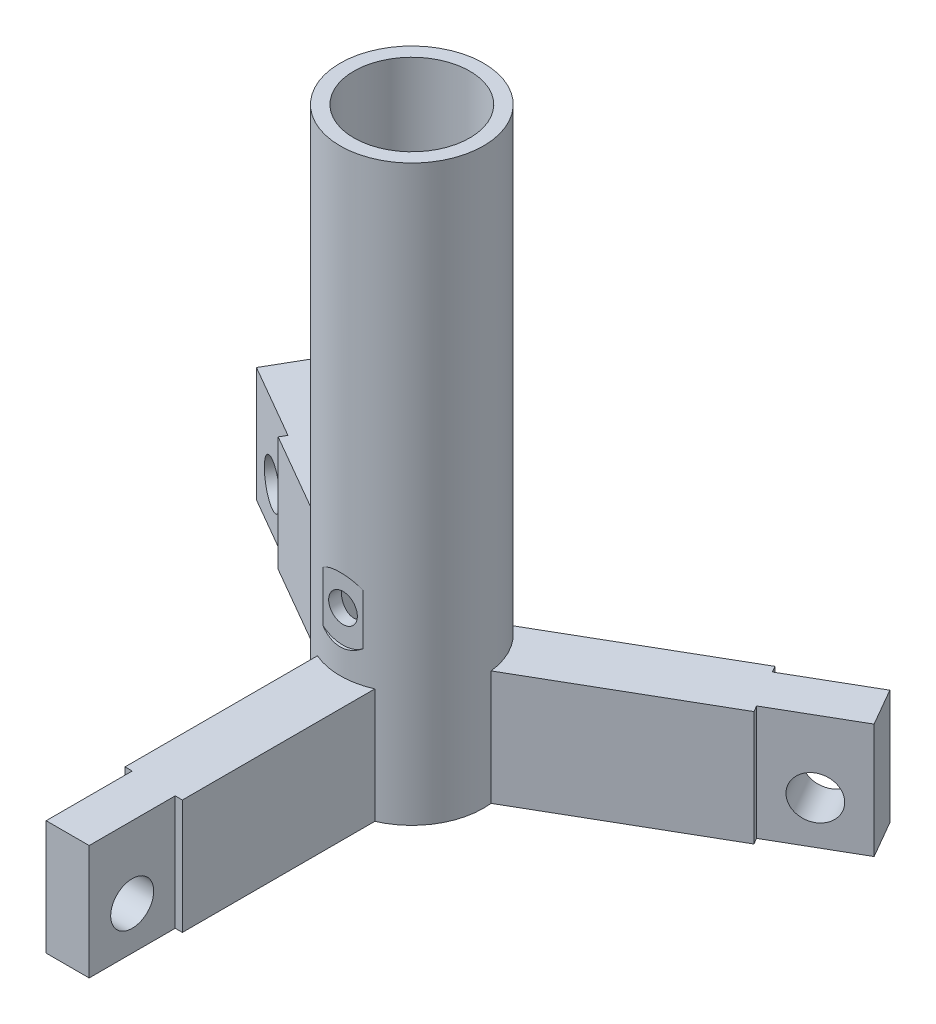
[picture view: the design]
ISO-10303-21;
HEADER;
FILE_DESCRIPTION(('STEP AP214'),'2;1');
FILE_NAME('part.step','',(''),(''),'','','');
FILE_SCHEMA(('AUTOMOTIVE_DESIGN { 1 0 10303 214 1 1 1 1 }'));
ENDSEC;
DATA;
#1=APPLICATION_CONTEXT('core data for automotive mechanical design processes');
#2=APPLICATION_PROTOCOL_DEFINITION('international standard','automotive_design',2000,#1);
#3=PRODUCT_CONTEXT('',#1,'mechanical');
#4=PRODUCT('Part','Part','',(#3));
#5=PRODUCT_RELATED_PRODUCT_CATEGORY('part','',(#4));
#6=PRODUCT_DEFINITION_FORMATION('','',#4);
#7=PRODUCT_DEFINITION_CONTEXT('part definition',#1,'design');
#8=PRODUCT_DEFINITION('design','',#6,#7);
#9=PRODUCT_DEFINITION_SHAPE('','',#8);
#10=(LENGTH_UNIT() NAMED_UNIT(*) SI_UNIT(.MILLI.,.METRE.));
#11=(NAMED_UNIT(*) PLANE_ANGLE_UNIT() SI_UNIT($,.RADIAN.));
#12=(NAMED_UNIT(*) SI_UNIT($,.STERADIAN.) SOLID_ANGLE_UNIT());
#13=UNCERTAINTY_MEASURE_WITH_UNIT(LENGTH_MEASURE(1.E-05),#10,'distance_accuracy_value','');
#14=(GEOMETRIC_REPRESENTATION_CONTEXT(3) GLOBAL_UNCERTAINTY_ASSIGNED_CONTEXT((#13)) GLOBAL_UNIT_ASSIGNED_CONTEXT((#10,
#11,#12)) REPRESENTATION_CONTEXT('',''));
#15=CARTESIAN_POINT('',(0.,0.,0.));
#16=DIRECTION('',(0.,0.,1.));
#17=DIRECTION('',(1.,0.,0.));
#18=AXIS2_PLACEMENT_3D('',#15,#16,#17);
#19=CARTESIAN_POINT('',(0.,38.1,15.24));
#20=DIRECTION('',(0.,0.,1.));
#21=DIRECTION('',(0.,-1.,0.));
#22=AXIS2_PLACEMENT_3D('',#19,#20,#21);
#23=PLANE('',#22);
#24=DIRECTION('',(0.,-1.,0.));
#25=VECTOR('',#24,1.);
#26=CARTESIAN_POINT('',(-4.44500000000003,127.,15.24));
#27=LINE('',#26,#25);
#28=CARTESIAN_POINT('',(-4.44500000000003,43.7005272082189,15.24));
#29=VERTEX_POINT('',#28);
#30=CARTESIAN_POINT('',(-4.44500000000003,32.4994727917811,15.24));
#31=VERTEX_POINT('',#30);
#32=EDGE_CURVE('E11',#29,#31,#27,.T.);
#33=ORIENTED_EDGE('',*,*,#32,.T.);
#34=CARTESIAN_POINT('',(0.,38.1,15.24));
#35=DIRECTION('',(0.,0.,1.));
#36=DIRECTION('',(0.,-1.,0.));
#37=AXIS2_PLACEMENT_3D('',#34,#35,#36);
#38=CIRCLE('',#37,7.1501);
#39=CARTESIAN_POINT('',(4.44500000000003,32.4994727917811,15.24));
#40=VERTEX_POINT('',#39);
#41=EDGE_CURVE('E215',#31,#40,#38,.T.);
#42=ORIENTED_EDGE('',*,*,#41,.T.);
#43=DIRECTION('',(0.,-1.,0.));
#44=VECTOR('',#43,1.);
#45=CARTESIAN_POINT('',(4.44500000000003,127.,15.24));
#46=LINE('',#45,#44);
#47=CARTESIAN_POINT('',(4.44500000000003,43.7005272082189,15.24));
#48=VERTEX_POINT('',#47);
#49=EDGE_CURVE('E46',#40,#48,#46,.F.);
#50=ORIENTED_EDGE('',*,*,#49,.T.);
#51=EDGE_CURVE('E213',#48,#29,#38,.T.);
#52=ORIENTED_EDGE('',*,*,#51,.T.);
#53=EDGE_LOOP('',(#33,#42,#50,#52));
#54=FACE_BOUND('',#53,.T.);
#55=CARTESIAN_POINT('',(0.,38.1,15.24));
#56=DIRECTION('',(0.,0.,1.));
#57=DIRECTION('',(0.,-1.,0.));
#58=AXIS2_PLACEMENT_3D('',#55,#56,#57);
#59=CIRCLE('',#58,3.17499725);
#60=CARTESIAN_POINT('',(0.,34.92500275,15.24));
#61=VERTEX_POINT('',#60);
#62=EDGE_CURVE('E590',#61,#61,#59,.T.);
#63=ORIENTED_EDGE('',*,*,#62,.F.);
#64=EDGE_LOOP('',(#63));
#65=FACE_BOUND('',#64,.T.);
#66=ADVANCED_FACE('F32',(#54,#65),#23,.T.);
#67=CARTESIAN_POINT('',(0.,127.,0.));
#68=DIRECTION('',(0.,-1.,0.));
#69=DIRECTION('',(0.,0.,-1.));
#70=AXIS2_PLACEMENT_3D('',#67,#68,#69);
#71=CYLINDRICAL_SURFACE('',#70,12.827);
#72=CARTESIAN_POINT('',(0.,0.,0.));
#73=DIRECTION('',(0.,1.,0.));
#74=DIRECTION('',(0.,0.,1.));
#75=AXIS2_PLACEMENT_3D('',#72,#73,#74);
#76=CIRCLE('',#75,12.827);
#77=CARTESIAN_POINT('',(0.,0.,12.827));
#78=VERTEX_POINT('',#77);
#79=EDGE_CURVE('E749',#78,#78,#76,.T.);
#80=ORIENTED_EDGE('',*,*,#79,.F.);
#81=EDGE_LOOP('',(#80));
#82=FACE_BOUND('',#81,.T.);
#83=CARTESIAN_POINT('',(0.,127.,0.));
#84=DIRECTION('',(0.,1.,0.));
#85=DIRECTION('',(0.,0.,1.));
#86=AXIS2_PLACEMENT_3D('',#83,#84,#85);
#87=CIRCLE('',#86,12.827);
#88=CARTESIAN_POINT('',(0.,127.,12.827));
#89=VERTEX_POINT('',#88);
#90=EDGE_CURVE('E770',#89,#89,#87,.T.);
#91=ORIENTED_EDGE('',*,*,#90,.T.);
#92=EDGE_LOOP('',(#91));
#93=FACE_BOUND('',#92,.T.);
#94=CARTESIAN_POINT('',(0.,34.92500275,12.827));
#95=CARTESIAN_POINT('',(0.175477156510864,34.9250077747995,12.8269969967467));
#96=CARTESIAN_POINT('',(0.351010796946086,34.9395992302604,12.823363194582));
#97=CARTESIAN_POINT('',(0.697051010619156,34.9974943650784,12.8092192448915));
#98=CARTESIAN_POINT('',(0.867554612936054,35.0408146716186,12.7987051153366));
#99=CARTESIAN_POINT('',(1.19848733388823,35.1546952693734,12.7719653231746));
#100=CARTESIAN_POINT('',(1.35892815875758,35.2252231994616,12.7557464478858));
#101=CARTESIAN_POINT('',(1.66570059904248,35.3914040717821,12.7193264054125));
#102=CARTESIAN_POINT('',(1.81203180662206,35.4870577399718,12.6991251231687));
#103=CARTESIAN_POINT('',(2.0893903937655,35.702818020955,12.6564783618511));
#104=CARTESIAN_POINT('',(2.22009183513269,35.8233369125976,12.6339988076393));
#105=CARTESIAN_POINT('',(2.45964846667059,36.0845236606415,12.5895565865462));
#106=CARTESIAN_POINT('',(2.56850123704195,36.2251937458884,12.5675939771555));
#107=CARTESIAN_POINT('',(2.76279553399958,36.5252104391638,12.526329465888));
#108=CARTESIAN_POINT('',(2.84787393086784,36.6847987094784,12.5070708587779));
#109=CARTESIAN_POINT('',(2.98986969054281,37.0165657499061,12.4738912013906));
#110=CARTESIAN_POINT('',(3.04679145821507,37.1887425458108,12.4599693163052));
#111=CARTESIAN_POINT('',(3.12974912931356,37.537219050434,12.4393893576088));
#112=CARTESIAN_POINT('',(3.15637034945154,37.7133711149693,12.4325938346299));
#113=CARTESIAN_POINT('',(3.17979416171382,38.0677620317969,12.4266244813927));
#114=CARTESIAN_POINT('',(3.17660150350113,38.2460005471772,12.4274494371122));
#115=CARTESIAN_POINT('',(3.14095552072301,38.5950303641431,12.4365041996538));
#116=CARTESIAN_POINT('',(3.10919816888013,38.7658980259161,12.4445578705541));
#117=CARTESIAN_POINT('',(3.0184338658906,39.099801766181,12.4668821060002));
#118=CARTESIAN_POINT('',(2.95942500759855,39.2628372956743,12.4811531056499));
#119=CARTESIAN_POINT('',(2.81523584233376,39.5783225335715,12.5144666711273));
#120=CARTESIAN_POINT('',(2.72980170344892,39.7306511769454,12.5335551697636));
#121=CARTESIAN_POINT('',(2.53536473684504,40.0190604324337,12.5743268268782));
#122=CARTESIAN_POINT('',(2.42635785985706,40.1551382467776,12.5960104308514));
#123=CARTESIAN_POINT('',(2.18425803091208,40.4111730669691,12.64027191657));
#124=CARTESIAN_POINT('',(2.05057737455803,40.5305736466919,12.6628578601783));
#125=CARTESIAN_POINT('',(1.76482059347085,40.7453665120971,12.7058325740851));
#126=CARTESIAN_POINT('',(1.61274392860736,40.8407580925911,12.7262212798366));
#127=CARTESIAN_POINT('',(1.2937277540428,41.0050237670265,12.7626025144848));
#128=CARTESIAN_POINT('',(1.12674066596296,41.0738089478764,12.7785802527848));
#129=CARTESIAN_POINT('',(0.783090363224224,41.1821778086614,12.804231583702));
#130=CARTESIAN_POINT('',(0.606428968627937,41.2217669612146,12.8139063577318));
#131=CARTESIAN_POINT('',(0.253203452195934,41.2697735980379,12.8256874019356));
#132=CARTESIAN_POINT('',(0.0767483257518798,41.2789490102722,12.827977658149));
#133=CARTESIAN_POINT('',(-0.275175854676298,41.2679444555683,12.8252549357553));
#134=CARTESIAN_POINT('',(-0.450644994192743,41.2477670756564,12.8202426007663));
#135=CARTESIAN_POINT('',(-0.792992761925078,41.1792548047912,12.8035956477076));
#136=CARTESIAN_POINT('',(-0.959959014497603,41.1313320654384,12.7920580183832));
#137=CARTESIAN_POINT('',(-1.28347476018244,41.0091590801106,12.7636599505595));
#138=CARTESIAN_POINT('',(-1.44002321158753,40.9349062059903,12.7467989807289));
#139=CARTESIAN_POINT('',(-1.74128504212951,40.7607026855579,12.7091826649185));
#140=CARTESIAN_POINT('',(-1.885743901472,40.6603257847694,12.688364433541));
#141=CARTESIAN_POINT('',(-2.15603644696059,40.4372697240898,12.6452442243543));
#142=CARTESIAN_POINT('',(-2.28186697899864,40.314586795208,12.6229419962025));
#143=CARTESIAN_POINT('',(-2.51444398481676,40.0468851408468,12.5787072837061));
#144=CARTESIAN_POINT('',(-2.62065929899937,39.9014005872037,12.5567965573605));
#145=CARTESIAN_POINT('',(-2.80716625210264,39.5942237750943,12.5164247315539));
#146=CARTESIAN_POINT('',(-2.88745904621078,39.4325322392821,12.4979634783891));
#147=CARTESIAN_POINT('',(-3.01924661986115,39.0984031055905,12.4667825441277));
#148=CARTESIAN_POINT('',(-3.0709120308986,38.9260361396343,12.4540289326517));
#149=CARTESIAN_POINT('',(-3.14443320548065,38.5746997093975,12.4356717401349));
#150=CARTESIAN_POINT('',(-3.16629533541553,38.3957316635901,12.4300666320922));
#151=CARTESIAN_POINT('',(-3.17926168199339,38.0416739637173,12.4267558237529));
#152=CARTESIAN_POINT('',(-3.17121422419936,37.8666169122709,12.4288322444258));
#153=CARTESIAN_POINT('',(-3.12652759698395,37.5204389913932,12.4401477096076));
#154=CARTESIAN_POINT('',(-3.08988898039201,37.3493180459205,12.449386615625));
#155=CARTESIAN_POINT('',(-2.98951914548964,37.0167714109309,12.4738658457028));
#156=CARTESIAN_POINT('',(-2.92594407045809,36.8552958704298,12.4890715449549));
#157=CARTESIAN_POINT('',(-2.77363006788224,36.545189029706,12.5237765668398));
#158=CARTESIAN_POINT('',(-2.68488771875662,36.3965594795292,12.5432764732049));
#159=CARTESIAN_POINT('',(-2.48208584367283,36.1122572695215,12.5849965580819));
#160=CARTESIAN_POINT('',(-2.3674363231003,35.9770137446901,12.6072735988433));
#161=CARTESIAN_POINT('',(-2.11722825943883,35.7274091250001,12.651695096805));
#162=CARTESIAN_POINT('',(-1.98166477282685,35.6130529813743,12.6738395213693));
#163=CARTESIAN_POINT('',(-1.69058803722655,35.4065031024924,12.7159671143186));
#164=CARTESIAN_POINT('',(-1.53476480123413,35.3147363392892,12.7359052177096));
#165=CARTESIAN_POINT('',(-1.20942520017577,35.1588466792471,12.7709004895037));
#166=CARTESIAN_POINT('',(-1.03991889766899,35.0947036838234,12.7859612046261));
#167=CARTESIAN_POINT('',(-0.725560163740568,35.0055663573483,12.8072389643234));
#168=CARTESIAN_POINT('',(-0.582224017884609,34.9754196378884,12.8145988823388));
#169=CARTESIAN_POINT('',(-0.29260486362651,34.935136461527,12.824480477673));
#170=CARTESIAN_POINT('',(-0.146322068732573,34.9249985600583,12.8270025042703));
#171=CARTESIAN_POINT('',(0.,34.92500275,12.827));
#172=B_SPLINE_CURVE_WITH_KNOTS('',3,(#94,#95,#96,#97,#98,#99,#100,#101,#102,#103,#104,#105,#106,
#107,#108,#109,#110,#111,#112,#113,#114,#115,#116,#117,#118,#119,#120,#121,#122,#123,#124,#125,
#126,#127,#128,#129,#130,#131,#132,#133,#134,#135,#136,#137,#138,#139,#140,#141,#142,#143,#144,
#145,#146,#147,#148,#149,#150,#151,#152,#153,#154,#155,#156,#157,#158,#159,#160,#161,#162,#163,
#164,#165,#166,#167,#168,#169,#170,#171),.UNSPECIFIED.,.T.,.F.,(4,2,2,2,2,2,2,2,2,2,2,2,2,2,2,2,
2,2,2,2,2,2,2,2,2,2,2,2,2,2,2,2,2,2,2,2,2,2,4),(0.,0.525895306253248,1.05209524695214,
1.57767123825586,2.10326241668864,2.63839228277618,3.1735813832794,3.71654644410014,
4.25942653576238,4.79163167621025,5.32375203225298,5.84324844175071,6.36278121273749,
6.88746812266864,7.4122452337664,7.95167980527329,8.49113021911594,9.03236810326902,
9.57350450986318,10.1010498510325,10.6285486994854,11.1484056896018,11.6683145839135,
12.1973057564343,12.7263863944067,13.2681789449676,13.8099473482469,14.3484508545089,
14.8868393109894,15.4100755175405,15.9333016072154,16.4535353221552,16.9738397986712,
17.5074648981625,18.0412163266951,18.5843921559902,19.1271721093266,19.5657228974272,
20.0042420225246),.UNSPECIFIED.);
#173=CARTESIAN_POINT('',(0.,34.92500275,12.827));
#174=VERTEX_POINT('',#173);
#175=EDGE_CURVE('E37',#174,#174,#172,.T.);
#176=ORIENTED_EDGE('',*,*,#175,.T.);
#177=EDGE_LOOP('',(#176));
#178=FACE_BOUND('',#177,.T.);
#179=ADVANCED_FACE('F340',(#82,#93,#178),#71,.F.);
#180=CARTESIAN_POINT('',(0.,127.,0.));
#181=DIRECTION('',(0.,-1.,0.));
#182=DIRECTION('',(0.,0.,-1.));
#183=AXIS2_PLACEMENT_3D('',#180,#181,#182);
#184=CYLINDRICAL_SURFACE('',#183,15.875);
#185=ORIENTED_EDGE('',*,*,#32,.F.);
#186=CARTESIAN_POINT('',(-4.44500000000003,43.7005272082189,15.24));
#187=CARTESIAN_POINT('',(-4.29462437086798,43.8198886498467,15.2838743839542));
#188=CARTESIAN_POINT('',(-4.13923548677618,43.9333326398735,15.3267669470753));
#189=CARTESIAN_POINT('',(-3.81921928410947,44.1476907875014,15.4096202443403));
#190=CARTESIAN_POINT('',(-3.65458852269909,44.2486002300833,15.4495798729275));
#191=CARTESIAN_POINT('',(-3.31656797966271,44.4373397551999,15.5256598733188));
#192=CARTESIAN_POINT('',(-3.1431572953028,44.5251364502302,15.5617703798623));
#193=CARTESIAN_POINT('',(-2.78898767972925,44.6866034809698,15.6291282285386));
#194=CARTESIAN_POINT('',(-2.60822967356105,44.7602755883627,15.6603761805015));
#195=CARTESIAN_POINT('',(-2.2399529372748,44.8930082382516,15.717285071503));
#196=CARTESIAN_POINT('',(-2.052416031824,44.9520255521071,15.7429294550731));
#197=CARTESIAN_POINT('',(-1.67239953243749,45.0545478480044,15.7878213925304));
#198=CARTESIAN_POINT('',(-1.47992013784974,45.0980534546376,15.8070692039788));
#199=CARTESIAN_POINT('',(-1.09179120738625,45.1690009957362,15.8386066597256));
#200=CARTESIAN_POINT('',(-0.896147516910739,45.1964696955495,15.8509078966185));
#201=CARTESIAN_POINT('',(-0.502943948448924,45.2351241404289,15.8682510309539));
#202=CARTESIAN_POINT('',(-0.3053841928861,45.2463109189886,15.8732933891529));
#203=CARTESIAN_POINT('',(0.079276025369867,45.2521054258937,15.8759032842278));
#204=CARTESIAN_POINT('',(0.266361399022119,45.2475811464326,15.8738621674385));
#205=CARTESIAN_POINT('',(0.639414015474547,45.2239040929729,15.863215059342));
#206=CARTESIAN_POINT('',(0.825381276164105,45.204751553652,15.854609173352));
#207=CARTESIAN_POINT('',(1.19500045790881,45.1520057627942,15.8310430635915));
#208=CARTESIAN_POINT('',(1.37865033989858,45.1184005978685,15.8160775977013));
#209=CARTESIAN_POINT('',(1.74219872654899,45.0371008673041,15.7801690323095));
#210=CARTESIAN_POINT('',(1.92209730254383,44.9894065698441,15.7592260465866));
#211=CARTESIAN_POINT('',(2.27536426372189,44.8808911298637,15.7120913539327));
#212=CARTESIAN_POINT('',(2.44877702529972,44.8201927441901,15.6859488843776));
#213=CARTESIAN_POINT('',(2.7898211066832,44.6859265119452,15.6288972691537));
#214=CARTESIAN_POINT('',(2.95744982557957,44.6123529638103,15.5979860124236));
#215=CARTESIAN_POINT('',(3.28565911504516,44.4530778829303,15.5321616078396));
#216=CARTESIAN_POINT('',(3.4462507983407,44.3673964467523,15.4972551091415));
#217=CARTESIAN_POINT('',(3.75988394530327,44.1844188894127,15.4241633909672));
#218=CARTESIAN_POINT('',(3.91292632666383,44.0871241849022,15.3859785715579));
#219=CARTESIAN_POINT('',(4.12735872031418,43.9391084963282,15.3292250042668));
#220=CARTESIAN_POINT('',(4.19209972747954,43.8928023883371,15.3116402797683));
#221=CARTESIAN_POINT('',(4.31984047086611,43.7981764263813,15.2760921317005));
#222=CARTESIAN_POINT('',(4.38284249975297,43.7498594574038,15.2581292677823));
#223=CARTESIAN_POINT('',(4.44500000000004,43.7005272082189,15.24));
#224=B_SPLINE_CURVE_WITH_KNOTS('',3,(#186,#187,#188,#189,#190,#191,#192,#193,#194,#195,#196,
#197,#198,#199,#200,#201,#202,#203,#204,#205,#206,#207,#208,#209,#210,#211,#212,#213,#214,#215,
#216,#217,#218,#219,#220,#221,#222,#223),.UNSPECIFIED.,.F.,.F.,(4,2,2,2,2,2,2,2,2,2,2,2,2,2,2,2,
2,2,4),(0.,0.590697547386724,1.1816166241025,1.77401553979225,2.36634010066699,2.96039167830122,
3.55441933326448,4.14745270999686,4.74044844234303,5.30121618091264,5.8619749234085,
6.42319679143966,6.98440797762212,7.5405380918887,8.09691510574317,8.65237926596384,
9.20777573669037,9.45228784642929,9.69646049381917),.UNSPECIFIED.);
#225=EDGE_CURVE('E218',#29,#48,#224,.T.);
#226=ORIENTED_EDGE('',*,*,#225,.T.);
#227=ORIENTED_EDGE('',*,*,#49,.F.);
#228=CARTESIAN_POINT('',(4.44500000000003,32.4994727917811,15.24));
#229=CARTESIAN_POINT('',(4.29465930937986,32.3801392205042,15.283864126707));
#230=CARTESIAN_POINT('',(4.13930809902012,32.2667204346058,15.3267468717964));
#231=CARTESIAN_POINT('',(3.8193780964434,32.0524111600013,15.4095803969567));
#232=CARTESIAN_POINT('',(3.65479624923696,31.9515248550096,15.4495301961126));
#233=CARTESIAN_POINT('',(3.31679123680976,31.7627757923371,15.5256125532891));
#234=CARTESIAN_POINT('',(3.14334292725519,31.6749531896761,15.5617332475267));
#235=CARTESIAN_POINT('',(2.78908878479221,31.5134376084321,15.6291108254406));
#236=CARTESIAN_POINT('',(2.60828353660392,31.4397435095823,15.6603680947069));
#237=CARTESIAN_POINT('',(2.23158372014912,31.3039756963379,15.7185780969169));
#238=CARTESIAN_POINT('',(2.03538172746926,31.2426319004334,15.7452512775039));
#239=CARTESIAN_POINT('',(1.63762289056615,31.1369210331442,15.7915769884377));
#240=CARTESIAN_POINT('',(1.4360656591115,31.0925551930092,15.8112290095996));
#241=CARTESIAN_POINT('',(1.02967451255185,31.0214288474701,15.842880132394));
#242=CARTESIAN_POINT('',(0.824847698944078,30.994634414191,15.854893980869));
#243=CARTESIAN_POINT('',(0.413343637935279,30.9588712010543,15.8709532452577));
#244=CARTESIAN_POINT('',(0.206666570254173,30.9499007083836,15.8749994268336));
#245=CARTESIAN_POINT('',(-0.190414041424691,30.9498993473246,15.8750005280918));
#246=CARTESIAN_POINT('',(-0.380819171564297,30.9575131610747,15.8715667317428));
#247=CARTESIAN_POINT('',(-0.76017538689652,30.9878787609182,15.8579247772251));
#248=CARTESIAN_POINT('',(-0.949126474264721,31.0106305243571,15.8477166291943));
#249=CARTESIAN_POINT('',(-1.32433664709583,31.0710450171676,15.8207829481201));
#250=CARTESIAN_POINT('',(-1.51059300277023,31.1087219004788,15.8040512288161));
#251=CARTESIAN_POINT('',(-1.87890519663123,31.1985813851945,15.7645059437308));
#252=CARTESIAN_POINT('',(-2.06096104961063,31.2507639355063,15.7416923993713));
#253=CARTESIAN_POINT('',(-2.41923738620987,31.3689730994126,15.6906209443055));
#254=CARTESIAN_POINT('',(-2.59547070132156,31.4349665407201,15.6623760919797));
#255=CARTESIAN_POINT('',(-2.94156228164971,31.5803079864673,15.601081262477));
#256=CARTESIAN_POINT('',(-3.11141767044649,31.6596619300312,15.5680291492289));
#257=CARTESIAN_POINT('',(-3.44336602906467,31.8308718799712,15.497986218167));
#258=CARTESIAN_POINT('',(-3.6054748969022,31.9227006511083,15.4610040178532));
#259=CARTESIAN_POINT('',(-3.92150870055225,32.11834224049,15.383882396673));
#260=CARTESIAN_POINT('',(-4.07543375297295,32.2221548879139,15.3437430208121));
#261=CARTESIAN_POINT('',(-4.29938207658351,32.3861762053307,15.2819153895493));
#262=CARTESIAN_POINT('',(-4.37277185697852,32.4421450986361,15.2610683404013));
#263=CARTESIAN_POINT('',(-4.44500000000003,32.4994727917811,15.24));
#264=B_SPLINE_CURVE_WITH_KNOTS('',3,(#228,#229,#230,#231,#232,#233,#234,#235,#236,#237,#238,
#239,#240,#241,#242,#243,#244,#245,#246,#247,#248,#249,#250,#251,#252,#253,#254,#255,#256,#257,
#258,#259,#260,#261,#262,#263),.UNSPECIFIED.,.F.,.F.,(4,2,2,2,2,2,2,2,2,2,2,2,2,2,2,2,2,4),(0.,
0.590559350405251,1.18131532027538,1.77385120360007,2.3663400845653,2.98734283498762,
3.60839061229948,4.22823567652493,4.84802117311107,5.41906592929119,5.99010983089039,
6.56169657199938,7.13328129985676,7.70350858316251,8.27399002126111,8.84324541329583,
9.41249269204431,9.69628073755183),.UNSPECIFIED.);
#265=EDGE_CURVE('E52',#40,#31,#264,.T.);
#266=ORIENTED_EDGE('',*,*,#265,.T.);
#267=EDGE_LOOP('',(#185,#226,#227,#266));
#268=FACE_BOUND('',#267,.T.);
#269=CARTESIAN_POINT('',(0.,127.,0.));
#270=DIRECTION('',(0.,1.,0.));
#271=DIRECTION('',(0.,0.,1.));
#272=AXIS2_PLACEMENT_3D('',#269,#270,#271);
#273=CIRCLE('',#272,15.875);
#274=CARTESIAN_POINT('',(0.,127.,15.875));
#275=VERTEX_POINT('',#274);
#276=EDGE_CURVE('E776',#275,#275,#273,.T.);
#277=ORIENTED_EDGE('',*,*,#276,.F.);
#278=EDGE_LOOP('',(#277));
#279=FACE_BOUND('',#278,.T.);
#280=DIRECTION('',(0.,-1.,0.));
#281=VECTOR('',#280,1.);
#282=CARTESIAN_POINT('',(9.42539061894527,127.,-12.7741002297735));
#283=LINE('',#282,#281);
#284=CARTESIAN_POINT('',(9.42539061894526,25.4,-12.7741002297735));
#285=VERTEX_POINT('',#284);
#286=CARTESIAN_POINT('',(9.42539061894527,0.,-12.7741002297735));
#287=VERTEX_POINT('',#286);
#288=EDGE_CURVE('E222',#285,#287,#283,.T.);
#289=ORIENTED_EDGE('',*,*,#288,.T.);
#290=CARTESIAN_POINT('',(0.,0.,0.));
#291=DIRECTION('',(0.,1.,0.));
#292=DIRECTION('',(0.,0.,1.));
#293=AXIS2_PLACEMENT_3D('',#290,#291,#292);
#294=CIRCLE('',#293,15.875);
#295=CARTESIAN_POINT('',(-9.42539061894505,0.,-12.7741002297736));
#296=VERTEX_POINT('',#295);
#297=EDGE_CURVE('E782',#287,#296,#294,.T.);
#298=ORIENTED_EDGE('',*,*,#297,.T.);
#299=DIRECTION('',(0.,-1.,0.));
#300=VECTOR('',#299,1.);
#301=CARTESIAN_POINT('',(-9.42539061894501,127.,-12.7741002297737));
#302=LINE('',#301,#300);
#303=CARTESIAN_POINT('',(-9.42539061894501,25.4,-12.7741002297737));
#304=VERTEX_POINT('',#303);
#305=EDGE_CURVE('E625',#304,#296,#302,.T.);
#306=ORIENTED_EDGE('',*,*,#305,.F.);
#307=CARTESIAN_POINT('',(0.,25.4,0.));
#308=DIRECTION('',(0.,-1.,0.));
#309=DIRECTION('',(1.,0.,0.));
#310=AXIS2_PLACEMENT_3D('',#307,#308,#309);
#311=CIRCLE('',#310,15.875);
#312=CARTESIAN_POINT('',(-15.7753906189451,25.4,-1.77557760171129));
#313=VERTEX_POINT('',#312);
#314=EDGE_CURVE('E697',#304,#313,#311,.F.);
#315=ORIENTED_EDGE('',*,*,#314,.T.);
#316=DIRECTION('',(0.,-1.,0.));
#317=VECTOR('',#316,1.);
#318=CARTESIAN_POINT('',(-15.7753906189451,127.,-1.77557760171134));
#319=LINE('',#318,#317);
#320=CARTESIAN_POINT('',(-15.7753906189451,0.,-1.77557760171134));
#321=VERTEX_POINT('',#320);
#322=EDGE_CURVE('E624',#313,#321,#319,.T.);
#323=ORIENTED_EDGE('',*,*,#322,.T.);
#324=CARTESIAN_POINT('',(-6.35000000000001,0.,14.5496778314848));
#325=VERTEX_POINT('',#324);
#326=EDGE_CURVE('E773',#321,#325,#294,.T.);
#327=ORIENTED_EDGE('',*,*,#326,.T.);
#328=DIRECTION('',(0.,-1.,0.));
#329=VECTOR('',#328,1.);
#330=CARTESIAN_POINT('',(-6.35000000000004,127.,14.5496778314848));
#331=LINE('',#330,#329);
#332=CARTESIAN_POINT('',(-6.35000000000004,25.4,14.5496778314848));
#333=VERTEX_POINT('',#332);
#334=EDGE_CURVE('E712',#333,#325,#331,.T.);
#335=ORIENTED_EDGE('',*,*,#334,.F.);
#336=CARTESIAN_POINT('',(0.,25.4,0.));
#337=DIRECTION('',(0.,-1.,0.));
#338=DIRECTION('',(0.,0.,-1.));
#339=AXIS2_PLACEMENT_3D('',#336,#337,#338);
#340=CIRCLE('',#339,15.875);
#341=CARTESIAN_POINT('',(6.34999999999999,25.4,14.5496778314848));
#342=VERTEX_POINT('',#341);
#343=EDGE_CURVE('E747',#333,#342,#340,.F.);
#344=ORIENTED_EDGE('',*,*,#343,.T.);
#345=DIRECTION('',(0.,-1.,0.));
#346=VECTOR('',#345,1.);
#347=CARTESIAN_POINT('',(6.34999999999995,127.,14.5496778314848));
#348=LINE('',#347,#346);
#349=CARTESIAN_POINT('',(6.34999999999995,0.,14.5496778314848));
#350=VERTEX_POINT('',#349);
#351=EDGE_CURVE('E708',#342,#350,#348,.T.);
#352=ORIENTED_EDGE('',*,*,#351,.T.);
#353=CARTESIAN_POINT('',(15.7753906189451,0.,-1.77557760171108));
#354=VERTEX_POINT('',#353);
#355=EDGE_CURVE('E780',#350,#354,#294,.T.);
#356=ORIENTED_EDGE('',*,*,#355,.T.);
#357=DIRECTION('',(0.,-1.,0.));
#358=VECTOR('',#357,1.);
#359=CARTESIAN_POINT('',(15.7753906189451,127.,-1.77557760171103));
#360=LINE('',#359,#358);
#361=CARTESIAN_POINT('',(15.7753906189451,25.4,-1.77557760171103));
#362=VERTEX_POINT('',#361);
#363=EDGE_CURVE('E593',#362,#354,#360,.T.);
#364=ORIENTED_EDGE('',*,*,#363,.F.);
#365=CARTESIAN_POINT('',(0.,25.4,0.));
#366=DIRECTION('',(0.,-1.,0.));
#367=DIRECTION('',(1.,0.,0.));
#368=AXIS2_PLACEMENT_3D('',#365,#366,#367);
#369=CIRCLE('',#368,15.875);
#370=EDGE_CURVE('E60',#362,#285,#369,.F.);
#371=ORIENTED_EDGE('',*,*,#370,.T.);
#372=EDGE_LOOP('',(#289,#298,#306,#315,#323,#327,#335,#344,#352,#356,#364,#371));
#373=FACE_BOUND('',#372,.T.);
#374=ADVANCED_FACE('F34',(#268,#279,#373),#184,.T.);
#375=CARTESIAN_POINT('',(0.,127.,0.));
#376=DIRECTION('',(0.,1.,0.));
#377=DIRECTION('',(0.,0.,1.));
#378=AXIS2_PLACEMENT_3D('',#375,#376,#377);
#379=PLANE('',#378);
#380=ORIENTED_EDGE('',*,*,#276,.T.);
#381=EDGE_LOOP('',(#380));
#382=FACE_BOUND('',#381,.T.);
#383=ORIENTED_EDGE('',*,*,#90,.F.);
#384=EDGE_LOOP('',(#383));
#385=FACE_BOUND('',#384,.T.);
#386=ADVANCED_FACE('F345',(#382,#385),#379,.T.);
#387=CARTESIAN_POINT('',(0.,0.,0.));
#388=DIRECTION('',(0.,1.,0.));
#389=DIRECTION('',(0.,0.,1.));
#390=AXIS2_PLACEMENT_3D('',#387,#388,#389);
#391=PLANE('',#390);
#392=ORIENTED_EDGE('',*,*,#297,.F.);
#393=DIRECTION('',(0.866025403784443,0.,-0.499999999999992));
#394=VECTOR('',#393,1.);
#395=CARTESIAN_POINT('',(-87.4510402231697,0.,43.1575331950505));
#396=LINE('',#395,#394);
#397=CARTESIAN_POINT('',(46.318351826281,0.,-34.0742613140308));
#398=VERTEX_POINT('',#397);
#399=EDGE_CURVE('E609',#287,#398,#396,.T.);
#400=ORIENTED_EDGE('',*,*,#399,.T.);
#401=DIRECTION('',(0.499999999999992,0.,0.866025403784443));
#402=VECTOR('',#401,1.);
#403=CARTESIAN_POINT('',(46.318351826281,0.,-34.0742613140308));
#404=LINE('',#403,#402);
#405=CARTESIAN_POINT('',(47.112101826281,0.,-32.699445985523));
#406=VERTEX_POINT('',#405);
#407=EDGE_CURVE('E597',#398,#406,#404,.T.);
#408=ORIENTED_EDGE('',*,*,#407,.T.);
#409=DIRECTION('',(0.866025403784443,0.,-0.499999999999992));
#410=VECTOR('',#409,1.);
#411=CARTESIAN_POINT('',(-47.2842508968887,0.,21.8003136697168));
#412=LINE('',#411,#410);
#413=CARTESIAN_POINT('',(63.6098857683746,0.,-42.2244459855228));
#414=VERTEX_POINT('',#413);
#415=EDGE_CURVE('E673',#406,#414,#412,.T.);
#416=ORIENTED_EDGE('',*,*,#415,.T.);
#417=DIRECTION('',(0.499999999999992,0.,0.866025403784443));
#418=VECTOR('',#417,1.);
#419=CARTESIAN_POINT('',(63.6098857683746,0.,-42.2244459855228));
#420=LINE('',#419,#418);
#421=CARTESIAN_POINT('',(68.3723857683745,0.,-33.975554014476));
#422=VERTEX_POINT('',#421);
#423=EDGE_CURVE('E669',#414,#422,#420,.T.);
#424=ORIENTED_EDGE('',*,*,#423,.T.);
#425=DIRECTION('',(0.866025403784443,0.,-0.499999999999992));
#426=VECTOR('',#425,1.);
#427=CARTESIAN_POINT('',(-42.5217508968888,0.,30.0492056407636));
#428=LINE('',#427,#426);
#429=CARTESIAN_POINT('',(51.8746018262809,0.,-24.4505540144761));
#430=VERTEX_POINT('',#429);
#431=EDGE_CURVE('E668',#430,#422,#428,.T.);
#432=ORIENTED_EDGE('',*,*,#431,.F.);
#433=CARTESIAN_POINT('',(52.6683518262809,0.,-23.0757386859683));
#434=VERTEX_POINT('',#433);
#435=EDGE_CURVE('E596',#430,#434,#404,.T.);
#436=ORIENTED_EDGE('',*,*,#435,.T.);
#437=DIRECTION('',(0.866025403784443,0.,-0.499999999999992));
#438=VECTOR('',#437,1.);
#439=CARTESIAN_POINT('',(-81.1010402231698,0.,54.1560558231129));
#440=LINE('',#439,#438);
#441=EDGE_CURVE('E616',#354,#434,#440,.T.);
#442=ORIENTED_EDGE('',*,*,#441,.F.);
#443=ORIENTED_EDGE('',*,*,#355,.F.);
#444=DIRECTION('',(0.,0.,1.));
#445=VECTOR('',#444,1.);
#446=CARTESIAN_POINT('',(6.35,0.,-15.876));
#447=LINE('',#446,#445);
#448=CARTESIAN_POINT('',(6.35,0.,57.15));
#449=VERTEX_POINT('',#448);
#450=EDGE_CURVE('E728',#350,#449,#447,.T.);
#451=ORIENTED_EDGE('',*,*,#450,.T.);
#452=DIRECTION('',(-1.,0.,0.));
#453=VECTOR('',#452,1.);
#454=CARTESIAN_POINT('',(6.35,0.,57.15));
#455=LINE('',#454,#453);
#456=CARTESIAN_POINT('',(4.7625,0.,57.15));
#457=VERTEX_POINT('',#456);
#458=EDGE_CURVE('E716',#449,#457,#455,.T.);
#459=ORIENTED_EDGE('',*,*,#458,.T.);
#460=DIRECTION('',(0.,0.,1.));
#461=VECTOR('',#460,1.);
#462=CARTESIAN_POINT('',(4.7625,0.,-15.876));
#463=LINE('',#462,#461);
#464=CARTESIAN_POINT('',(4.7625,0.,76.2));
#465=VERTEX_POINT('',#464);
#466=EDGE_CURVE('E765',#457,#465,#463,.T.);
#467=ORIENTED_EDGE('',*,*,#466,.T.);
#468=DIRECTION('',(-1.,0.,0.));
#469=VECTOR('',#468,1.);
#470=CARTESIAN_POINT('',(4.7625,0.,76.2));
#471=LINE('',#470,#469);
#472=CARTESIAN_POINT('',(-4.7625,0.,76.2));
#473=VERTEX_POINT('',#472);
#474=EDGE_CURVE('E760',#465,#473,#471,.T.);
#475=ORIENTED_EDGE('',*,*,#474,.T.);
#476=DIRECTION('',(0.,0.,1.));
#477=VECTOR('',#476,1.);
#478=CARTESIAN_POINT('',(-4.7625,0.,-15.876));
#479=LINE('',#478,#477);
#480=CARTESIAN_POINT('',(-4.7625,0.,57.15));
#481=VERTEX_POINT('',#480);
#482=EDGE_CURVE('E763',#481,#473,#479,.T.);
#483=ORIENTED_EDGE('',*,*,#482,.F.);
#484=CARTESIAN_POINT('',(-6.35,0.,57.15));
#485=VERTEX_POINT('',#484);
#486=EDGE_CURVE('E715',#481,#485,#455,.T.);
#487=ORIENTED_EDGE('',*,*,#486,.T.);
#488=DIRECTION('',(0.,0.,1.));
#489=VECTOR('',#488,1.);
#490=CARTESIAN_POINT('',(-6.35,0.,-15.876));
#491=LINE('',#490,#489);
#492=EDGE_CURVE('E735',#325,#485,#491,.T.);
#493=ORIENTED_EDGE('',*,*,#492,.F.);
#494=ORIENTED_EDGE('',*,*,#326,.F.);
#495=DIRECTION('',(-0.866025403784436,0.,-0.500000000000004));
#496=VECTOR('',#495,1.);
#497=CARTESIAN_POINT('',(81.1010402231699,0.,54.1560558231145));
#498=LINE('',#497,#496);
#499=CARTESIAN_POINT('',(-52.6683518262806,0.,-23.0757386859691));
#500=VERTEX_POINT('',#499);
#501=EDGE_CURVE('E641',#321,#500,#498,.T.);
#502=ORIENTED_EDGE('',*,*,#501,.T.);
#503=DIRECTION('',(0.500000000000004,0.,-0.866025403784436));
#504=VECTOR('',#503,1.);
#505=CARTESIAN_POINT('',(-52.6683518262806,0.,-23.0757386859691));
#506=LINE('',#505,#504);
#507=CARTESIAN_POINT('',(-51.8746018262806,0.,-24.4505540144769));
#508=VERTEX_POINT('',#507);
#509=EDGE_CURVE('E629',#500,#508,#506,.T.);
#510=ORIENTED_EDGE('',*,*,#509,.T.);
#511=DIRECTION('',(-0.866025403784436,0.,-0.500000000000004));
#512=VECTOR('',#511,1.);
#513=CARTESIAN_POINT('',(42.5217508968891,0.,30.0492056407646));
#514=LINE('',#513,#512);
#515=CARTESIAN_POINT('',(-68.3723857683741,0.,-33.9755540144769));
#516=VERTEX_POINT('',#515);
#517=EDGE_CURVE('E694',#508,#516,#514,.T.);
#518=ORIENTED_EDGE('',*,*,#517,.T.);
#519=DIRECTION('',(0.500000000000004,0.,-0.866025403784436));
#520=VECTOR('',#519,1.);
#521=CARTESIAN_POINT('',(-68.3723857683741,0.,-33.9755540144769));
#522=LINE('',#521,#520);
#523=CARTESIAN_POINT('',(-63.609885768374,0.,-42.2244459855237));
#524=VERTEX_POINT('',#523);
#525=EDGE_CURVE('E690',#516,#524,#522,.T.);
#526=ORIENTED_EDGE('',*,*,#525,.T.);
#527=DIRECTION('',(-0.866025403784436,0.,-0.500000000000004));
#528=VECTOR('',#527,1.);
#529=CARTESIAN_POINT('',(47.2842508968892,0.,21.8003136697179));
#530=LINE('',#529,#528);
#531=CARTESIAN_POINT('',(-47.1121018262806,0.,-32.6994459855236));
#532=VERTEX_POINT('',#531);
#533=EDGE_CURVE('E686',#532,#524,#530,.T.);
#534=ORIENTED_EDGE('',*,*,#533,.F.);
#535=CARTESIAN_POINT('',(-46.3183518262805,0.,-34.0742613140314));
#536=VERTEX_POINT('',#535);
#537=EDGE_CURVE('E628',#532,#536,#506,.T.);
#538=ORIENTED_EDGE('',*,*,#537,.T.);
#539=DIRECTION('',(-0.866025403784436,0.,-0.500000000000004));
#540=VECTOR('',#539,1.);
#541=CARTESIAN_POINT('',(87.4510402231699,0.,43.1575331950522));
#542=LINE('',#541,#540);
#543=EDGE_CURVE('E648',#296,#536,#542,.T.);
#544=ORIENTED_EDGE('',*,*,#543,.F.);
#545=EDGE_LOOP('',(#392,#400,#408,#416,#424,#432,#436,#442,#443,#451,#459,#467,#475,#483,#487,
#493,#494,#502,#510,#518,#526,#534,#538,#544));
#546=FACE_BOUND('',#545,.T.);
#547=ORIENTED_EDGE('',*,*,#79,.T.);
#548=EDGE_LOOP('',(#547));
#549=FACE_BOUND('',#548,.T.);
#550=ADVANCED_FACE('F329',(#546,#549),#391,.F.);
#551=CARTESIAN_POINT('',(-4.7625,25.4,76.2));
#552=DIRECTION('',(0.,0.,-1.));
#553=DIRECTION('',(-1.,0.,0.));
#554=AXIS2_PLACEMENT_3D('',#551,#552,#553);
#555=PLANE('',#554);
#556=DIRECTION('',(0.,1.,0.));
#557=VECTOR('',#556,1.);
#558=CARTESIAN_POINT('',(-4.7625,0.,76.2));
#559=LINE('',#558,#557);
#560=CARTESIAN_POINT('',(-4.7625,25.4,76.2));
#561=VERTEX_POINT('',#560);
#562=EDGE_CURVE('E751',#473,#561,#559,.T.);
#563=ORIENTED_EDGE('',*,*,#562,.F.);
#564=ORIENTED_EDGE('',*,*,#474,.F.);
#565=DIRECTION('',(0.,1.,0.));
#566=VECTOR('',#565,1.);
#567=CARTESIAN_POINT('',(4.7625,0.,76.2));
#568=LINE('',#567,#566);
#569=CARTESIAN_POINT('',(4.7625,25.4,76.2));
#570=VERTEX_POINT('',#569);
#571=EDGE_CURVE('E757',#465,#570,#568,.T.);
#572=ORIENTED_EDGE('',*,*,#571,.T.);
#573=DIRECTION('',(1.,0.,0.));
#574=VECTOR('',#573,1.);
#575=CARTESIAN_POINT('',(-4.7625,25.4,76.2));
#576=LINE('',#575,#574);
#577=EDGE_CURVE('E754',#561,#570,#576,.T.);
#578=ORIENTED_EDGE('',*,*,#577,.F.);
#579=EDGE_LOOP('',(#563,#564,#572,#578));
#580=FACE_BOUND('',#579,.T.);
#581=ADVANCED_FACE('F325',(#580),#555,.F.);
#582=CARTESIAN_POINT('',(4.7625,0.,-15.876));
#583=DIRECTION('',(1.,0.,0.));
#584=DIRECTION('',(0.,1.,0.));
#585=AXIS2_PLACEMENT_3D('',#582,#583,#584);
#586=PLANE('',#585);
#587=DIRECTION('',(0.,-1.,0.));
#588=VECTOR('',#587,1.);
#589=CARTESIAN_POINT('',(4.7625,0.,57.15));
#590=LINE('',#589,#588);
#591=CARTESIAN_POINT('',(4.7625,25.4,57.15));
#592=VERTEX_POINT('',#591);
#593=EDGE_CURVE('E738',#592,#457,#590,.T.);
#594=ORIENTED_EDGE('',*,*,#593,.F.);
#595=DIRECTION('',(0.,0.,1.));
#596=VECTOR('',#595,1.);
#597=CARTESIAN_POINT('',(4.7625,25.4,-15.876));
#598=LINE('',#597,#596);
#599=EDGE_CURVE('E767',#592,#570,#598,.T.);
#600=ORIENTED_EDGE('',*,*,#599,.T.);
#601=ORIENTED_EDGE('',*,*,#571,.F.);
#602=ORIENTED_EDGE('',*,*,#466,.F.);
#603=EDGE_LOOP('',(#594,#600,#601,#602));
#604=FACE_BOUND('',#603,.T.);
#605=CARTESIAN_POINT('',(4.7625,9.525,66.675));
#606=DIRECTION('',(1.,0.,0.));
#607=DIRECTION('',(0.,1.,0.));
#608=AXIS2_PLACEMENT_3D('',#605,#606,#607);
#609=CIRCLE('',#608,4.7625);
#610=CARTESIAN_POINT('',(4.7625,14.2875,66.675));
#611=VERTEX_POINT('',#610);
#612=EDGE_CURVE('E743',#611,#611,#609,.T.);
#613=ORIENTED_EDGE('',*,*,#612,.F.);
#614=EDGE_LOOP('',(#613));
#615=FACE_BOUND('',#614,.T.);
#616=ADVANCED_FACE('F328',(#604,#615),#586,.T.);
#617=CARTESIAN_POINT('',(-4.7625,25.4,-15.876));
#618=DIRECTION('',(0.,-1.,0.));
#619=DIRECTION('',(0.,0.,-1.));
#620=AXIS2_PLACEMENT_3D('',#617,#618,#619);
#621=PLANE('',#620);
#622=ORIENTED_EDGE('',*,*,#599,.F.);
#623=DIRECTION('',(1.,0.,0.));
#624=VECTOR('',#623,1.);
#625=CARTESIAN_POINT('',(-6.35000000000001,25.4,57.15));
#626=LINE('',#625,#624);
#627=CARTESIAN_POINT('',(6.34999999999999,25.4,57.15));
#628=VERTEX_POINT('',#627);
#629=EDGE_CURVE('E721',#592,#628,#626,.T.);
#630=ORIENTED_EDGE('',*,*,#629,.T.);
#631=DIRECTION('',(0.,0.,1.));
#632=VECTOR('',#631,1.);
#633=CARTESIAN_POINT('',(6.34999999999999,25.4,-15.876));
#634=LINE('',#633,#632);
#635=EDGE_CURVE('E730',#342,#628,#634,.T.);
#636=ORIENTED_EDGE('',*,*,#635,.F.);
#637=ORIENTED_EDGE('',*,*,#343,.F.);
#638=DIRECTION('',(0.,0.,1.));
#639=VECTOR('',#638,1.);
#640=CARTESIAN_POINT('',(-6.35000000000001,25.4,-15.876));
#641=LINE('',#640,#639);
#642=CARTESIAN_POINT('',(-6.35000000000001,25.4,57.15));
#643=VERTEX_POINT('',#642);
#644=EDGE_CURVE('E733',#333,#643,#641,.T.);
#645=ORIENTED_EDGE('',*,*,#644,.T.);
#646=CARTESIAN_POINT('',(-4.7625,25.4,57.15));
#647=VERTEX_POINT('',#646);
#648=EDGE_CURVE('E722',#643,#647,#626,.T.);
#649=ORIENTED_EDGE('',*,*,#648,.T.);
#650=DIRECTION('',(0.,0.,1.));
#651=VECTOR('',#650,1.);
#652=CARTESIAN_POINT('',(-4.7625,25.4,-15.876));
#653=LINE('',#652,#651);
#654=EDGE_CURVE('E750',#647,#561,#653,.T.);
#655=ORIENTED_EDGE('',*,*,#654,.T.);
#656=ORIENTED_EDGE('',*,*,#577,.T.);
#657=EDGE_LOOP('',(#622,#630,#636,#637,#645,#649,#655,#656));
#658=FACE_BOUND('',#657,.T.);
#659=ADVANCED_FACE('F333',(#658),#621,.F.);
#660=CARTESIAN_POINT('',(-4.7625,0.,-15.876));
#661=DIRECTION('',(1.,0.,0.));
#662=DIRECTION('',(0.,1.,0.));
#663=AXIS2_PLACEMENT_3D('',#660,#661,#662);
#664=PLANE('',#663);
#665=CARTESIAN_POINT('',(-4.7625,9.525,66.675));
#666=DIRECTION('',(1.,0.,0.));
#667=DIRECTION('',(0.,1.,0.));
#668=AXIS2_PLACEMENT_3D('',#665,#666,#667);
#669=CIRCLE('',#668,4.7625);
#670=CARTESIAN_POINT('',(-4.7625,14.2875,66.675));
#671=VERTEX_POINT('',#670);
#672=EDGE_CURVE('E746',#671,#671,#669,.T.);
#673=ORIENTED_EDGE('',*,*,#672,.T.);
#674=EDGE_LOOP('',(#673));
#675=FACE_BOUND('',#674,.T.);
#676=ORIENTED_EDGE('',*,*,#654,.F.);
#677=DIRECTION('',(0.,-1.,0.));
#678=VECTOR('',#677,1.);
#679=CARTESIAN_POINT('',(-4.7625,0.,57.15));
#680=LINE('',#679,#678);
#681=EDGE_CURVE('E779',#647,#481,#680,.T.);
#682=ORIENTED_EDGE('',*,*,#681,.T.);
#683=ORIENTED_EDGE('',*,*,#482,.T.);
#684=ORIENTED_EDGE('',*,*,#562,.T.);
#685=EDGE_LOOP('',(#676,#682,#683,#684));
#686=FACE_BOUND('',#685,.T.);
#687=ADVANCED_FACE('F323',(#675,#686),#664,.F.);
#688=CARTESIAN_POINT('',(-15.875,9.525,66.675));
#689=DIRECTION('',(1.,0.,0.));
#690=DIRECTION('',(0.,1.,0.));
#691=AXIS2_PLACEMENT_3D('',#688,#689,#690);
#692=CYLINDRICAL_SURFACE('',#691,4.7625);
#693=ORIENTED_EDGE('',*,*,#612,.T.);
#694=EDGE_LOOP('',(#693));
#695=FACE_BOUND('',#694,.T.);
#696=ORIENTED_EDGE('',*,*,#672,.F.);
#697=EDGE_LOOP('',(#696));
#698=FACE_BOUND('',#697,.T.);
#699=ADVANCED_FACE('F320',(#695,#698),#692,.F.);
#700=CARTESIAN_POINT('',(-6.35,0.,57.15));
#701=DIRECTION('',(0.,0.,1.));
#702=DIRECTION('',(1.,0.,0.));
#703=AXIS2_PLACEMENT_3D('',#700,#701,#702);
#704=PLANE('',#703);
#705=ORIENTED_EDGE('',*,*,#681,.F.);
#706=ORIENTED_EDGE('',*,*,#648,.F.);
#707=DIRECTION('',(0.,-1.,0.));
#708=VECTOR('',#707,1.);
#709=CARTESIAN_POINT('',(-6.35000000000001,25.4,57.15));
#710=LINE('',#709,#708);
#711=EDGE_CURVE('E718',#643,#485,#710,.T.);
#712=ORIENTED_EDGE('',*,*,#711,.T.);
#713=ORIENTED_EDGE('',*,*,#486,.F.);
#714=EDGE_LOOP('',(#705,#706,#712,#713));
#715=FACE_BOUND('',#714,.T.);
#716=ADVANCED_FACE('F313',(#715),#704,.T.);
#717=CARTESIAN_POINT('',(-6.35000000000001,25.4,-15.876));
#718=DIRECTION('',(-1.,0.,0.));
#719=DIRECTION('',(0.,-1.,0.));
#720=AXIS2_PLACEMENT_3D('',#717,#718,#719);
#721=PLANE('',#720);
#722=ORIENTED_EDGE('',*,*,#644,.F.);
#723=ORIENTED_EDGE('',*,*,#334,.T.);
#724=ORIENTED_EDGE('',*,*,#492,.T.);
#725=ORIENTED_EDGE('',*,*,#711,.F.);
#726=EDGE_LOOP('',(#722,#723,#724,#725));
#727=FACE_BOUND('',#726,.T.);
#728=ADVANCED_FACE('F311',(#727),#721,.T.);
#729=ORIENTED_EDGE('',*,*,#629,.F.);
#730=ORIENTED_EDGE('',*,*,#593,.T.);
#731=ORIENTED_EDGE('',*,*,#458,.F.);
#732=DIRECTION('',(0.,-1.,0.));
#733=VECTOR('',#732,1.);
#734=CARTESIAN_POINT('',(6.34999999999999,25.4,57.15));
#735=LINE('',#734,#733);
#736=EDGE_CURVE('E725',#628,#449,#735,.T.);
#737=ORIENTED_EDGE('',*,*,#736,.F.);
#738=EDGE_LOOP('',(#729,#730,#731,#737));
#739=FACE_BOUND('',#738,.T.);
#740=ADVANCED_FACE('F308',(#739),#704,.T.);
#741=CARTESIAN_POINT('',(6.34999999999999,25.4,-15.876));
#742=DIRECTION('',(-1.,0.,0.));
#743=DIRECTION('',(0.,-1.,0.));
#744=AXIS2_PLACEMENT_3D('',#741,#742,#743);
#745=PLANE('',#744);
#746=ORIENTED_EDGE('',*,*,#351,.F.);
#747=ORIENTED_EDGE('',*,*,#635,.T.);
#748=ORIENTED_EDGE('',*,*,#736,.T.);
#749=ORIENTED_EDGE('',*,*,#450,.F.);
#750=EDGE_LOOP('',(#746,#747,#748,#749));
#751=FACE_BOUND('',#750,.T.);
#752=ADVANCED_FACE('F306',(#751),#745,.F.);
#753=CARTESIAN_POINT('',(47.2842508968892,0.,21.8003136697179));
#754=DIRECTION('',(-0.500000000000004,0.,0.866025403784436));
#755=DIRECTION('',(0.866025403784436,0.,0.500000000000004));
#756=AXIS2_PLACEMENT_3D('',#753,#754,#755);
#757=PLANE('',#756);
#758=CARTESIAN_POINT('',(-55.3609937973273,9.525,-37.4619459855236));
#759=DIRECTION('',(-0.500000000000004,0.,0.866025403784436));
#760=DIRECTION('',(0.866025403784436,0.,0.500000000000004));
#761=AXIS2_PLACEMENT_3D('',#758,#759,#760);
#762=CIRCLE('',#761,4.7625);
#763=CARTESIAN_POINT('',(-51.2365478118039,9.525,-35.0806959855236));
#764=VERTEX_POINT('',#763);
#765=EDGE_CURVE('E665',#764,#764,#762,.T.);
#766=ORIENTED_EDGE('',*,*,#765,.T.);
#767=EDGE_LOOP('',(#766));
#768=FACE_BOUND('',#767,.T.);
#769=DIRECTION('',(-0.866025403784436,0.,-0.500000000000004));
#770=VECTOR('',#769,1.);
#771=CARTESIAN_POINT('',(47.2842508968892,25.4,21.8003136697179));
#772=LINE('',#771,#770);
#773=CARTESIAN_POINT('',(-47.1121018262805,25.4,-32.6994459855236));
#774=VERTEX_POINT('',#773);
#775=CARTESIAN_POINT('',(-63.609885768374,25.4,-42.2244459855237));
#776=VERTEX_POINT('',#775);
#777=EDGE_CURVE('E702',#774,#776,#772,.T.);
#778=ORIENTED_EDGE('',*,*,#777,.F.);
#779=DIRECTION('',(0.,-1.,0.));
#780=VECTOR('',#779,1.);
#781=CARTESIAN_POINT('',(-47.1121018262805,0.,-32.6994459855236));
#782=LINE('',#781,#780);
#783=EDGE_CURVE('E651',#774,#532,#782,.T.);
#784=ORIENTED_EDGE('',*,*,#783,.T.);
#785=ORIENTED_EDGE('',*,*,#533,.T.);
#786=DIRECTION('',(0.,1.,0.));
#787=VECTOR('',#786,1.);
#788=CARTESIAN_POINT('',(-63.609885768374,0.,-42.2244459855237));
#789=LINE('',#788,#787);
#790=EDGE_CURVE('E703',#524,#776,#789,.T.);
#791=ORIENTED_EDGE('',*,*,#790,.T.);
#792=EDGE_LOOP('',(#778,#784,#785,#791));
#793=FACE_BOUND('',#792,.T.);
#794=ADVANCED_FACE('F302',(#768,#793),#757,.F.);
#795=CARTESIAN_POINT('',(47.2842508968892,25.4,21.8003136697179));
#796=DIRECTION('',(0.,-1.,0.));
#797=DIRECTION('',(1.,0.,0.));
#798=AXIS2_PLACEMENT_3D('',#795,#796,#797);
#799=PLANE('',#798);
#800=DIRECTION('',(-0.866025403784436,0.,-0.500000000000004));
#801=VECTOR('',#800,1.);
#802=CARTESIAN_POINT('',(42.5217508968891,25.4,30.0492056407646));
#803=LINE('',#802,#801);
#804=CARTESIAN_POINT('',(-51.8746018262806,25.4,-24.4505540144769));
#805=VERTEX_POINT('',#804);
#806=CARTESIAN_POINT('',(-68.3723857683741,25.4,-33.9755540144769));
#807=VERTEX_POINT('',#806);
#808=EDGE_CURVE('E701',#805,#807,#803,.T.);
#809=ORIENTED_EDGE('',*,*,#808,.F.);
#810=DIRECTION('',(-0.500000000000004,0.,0.866025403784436));
#811=VECTOR('',#810,1.);
#812=CARTESIAN_POINT('',(-46.3183518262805,25.4,-34.0742613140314));
#813=LINE('',#812,#811);
#814=CARTESIAN_POINT('',(-52.6683518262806,25.4,-23.0757386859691));
#815=VERTEX_POINT('',#814);
#816=EDGE_CURVE('E634',#805,#815,#813,.T.);
#817=ORIENTED_EDGE('',*,*,#816,.T.);
#818=DIRECTION('',(-0.866025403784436,0.,-0.500000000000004));
#819=VECTOR('',#818,1.);
#820=CARTESIAN_POINT('',(81.1010402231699,25.4,54.1560558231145));
#821=LINE('',#820,#819);
#822=EDGE_CURVE('E643',#313,#815,#821,.T.);
#823=ORIENTED_EDGE('',*,*,#822,.F.);
#824=ORIENTED_EDGE('',*,*,#314,.F.);
#825=DIRECTION('',(-0.866025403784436,0.,-0.500000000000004));
#826=VECTOR('',#825,1.);
#827=CARTESIAN_POINT('',(87.4510402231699,25.4,43.1575331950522));
#828=LINE('',#827,#826);
#829=CARTESIAN_POINT('',(-46.3183518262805,25.4,-34.0742613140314));
#830=VERTEX_POINT('',#829);
#831=EDGE_CURVE('E646',#304,#830,#828,.T.);
#832=ORIENTED_EDGE('',*,*,#831,.T.);
#833=EDGE_CURVE('E635',#830,#774,#813,.T.);
#834=ORIENTED_EDGE('',*,*,#833,.T.);
#835=ORIENTED_EDGE('',*,*,#777,.T.);
#836=DIRECTION('',(-0.500000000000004,0.,0.866025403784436));
#837=VECTOR('',#836,1.);
#838=CARTESIAN_POINT('',(-63.609885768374,25.4,-42.2244459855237));
#839=LINE('',#838,#837);
#840=EDGE_CURVE('E698',#776,#807,#839,.T.);
#841=ORIENTED_EDGE('',*,*,#840,.T.);
#842=EDGE_LOOP('',(#809,#817,#823,#824,#832,#834,#835,#841));
#843=FACE_BOUND('',#842,.T.);
#844=ADVANCED_FACE('F298',(#843),#799,.F.);
#845=CARTESIAN_POINT('',(42.5217508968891,0.,30.0492056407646));
#846=DIRECTION('',(-0.500000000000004,0.,0.866025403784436));
#847=DIRECTION('',(0.866025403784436,0.,0.500000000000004));
#848=AXIS2_PLACEMENT_3D('',#845,#846,#847);
#849=PLANE('',#848);
#850=DIRECTION('',(0.,-1.,0.));
#851=VECTOR('',#850,1.);
#852=CARTESIAN_POINT('',(-51.8746018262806,0.,-24.4505540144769));
#853=LINE('',#852,#851);
#854=EDGE_CURVE('E787',#805,#508,#853,.T.);
#855=ORIENTED_EDGE('',*,*,#854,.F.);
#856=ORIENTED_EDGE('',*,*,#808,.T.);
#857=DIRECTION('',(0.,1.,0.));
#858=VECTOR('',#857,1.);
#859=CARTESIAN_POINT('',(-68.3723857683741,0.,-33.9755540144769));
#860=LINE('',#859,#858);
#861=EDGE_CURVE('E693',#516,#807,#860,.T.);
#862=ORIENTED_EDGE('',*,*,#861,.F.);
#863=ORIENTED_EDGE('',*,*,#517,.F.);
#864=EDGE_LOOP('',(#855,#856,#862,#863));
#865=FACE_BOUND('',#864,.T.);
#866=CARTESIAN_POINT('',(-60.1234937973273,9.525,-29.2130540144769));
#867=DIRECTION('',(-0.500000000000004,0.,0.866025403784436));
#868=DIRECTION('',(0.,1.,0.));
#869=AXIS2_PLACEMENT_3D('',#866,#867,#868);
#870=CIRCLE('',#869,4.7625);
#871=CARTESIAN_POINT('',(-60.1234937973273,14.2875,-29.2130540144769));
#872=VERTEX_POINT('',#871);
#873=EDGE_CURVE('E662',#872,#872,#870,.T.);
#874=ORIENTED_EDGE('',*,*,#873,.F.);
#875=EDGE_LOOP('',(#874));
#876=FACE_BOUND('',#875,.T.);
#877=ADVANCED_FACE('F294',(#865,#876),#849,.T.);
#878=CARTESIAN_POINT('',(-63.609885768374,25.4,-42.2244459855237));
#879=DIRECTION('',(0.866025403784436,0.,0.500000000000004));
#880=DIRECTION('',(0.500000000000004,0.,-0.866025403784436));
#881=AXIS2_PLACEMENT_3D('',#878,#879,#880);
#882=PLANE('',#881);
#883=ORIENTED_EDGE('',*,*,#790,.F.);
#884=ORIENTED_EDGE('',*,*,#525,.F.);
#885=ORIENTED_EDGE('',*,*,#861,.T.);
#886=ORIENTED_EDGE('',*,*,#840,.F.);
#887=EDGE_LOOP('',(#883,#884,#885,#886));
#888=FACE_BOUND('',#887,.T.);
#889=ADVANCED_FACE('F290',(#888),#882,.F.);
#890=CARTESIAN_POINT('',(-42.5217508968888,0.,30.0492056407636));
#891=DIRECTION('',(-0.499999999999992,0.,-0.866025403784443));
#892=DIRECTION('',(-0.866025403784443,0.,0.499999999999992));
#893=AXIS2_PLACEMENT_3D('',#890,#891,#892);
#894=PLANE('',#893);
#895=CARTESIAN_POINT('',(60.1234937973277,9.525,-29.2130540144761));
#896=DIRECTION('',(-0.499999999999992,0.,-0.866025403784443));
#897=DIRECTION('',(-0.866025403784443,0.,0.499999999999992));
#898=AXIS2_PLACEMENT_3D('',#895,#896,#897);
#899=CIRCLE('',#898,4.7625);
#900=CARTESIAN_POINT('',(55.9990478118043,9.525,-26.8318040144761));
#901=VERTEX_POINT('',#900);
#902=EDGE_CURVE('E659',#901,#901,#899,.T.);
#903=ORIENTED_EDGE('',*,*,#902,.T.);
#904=EDGE_LOOP('',(#903));
#905=FACE_BOUND('',#904,.T.);
#906=DIRECTION('',(0.866025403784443,0.,-0.499999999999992));
#907=VECTOR('',#906,1.);
#908=CARTESIAN_POINT('',(-42.5217508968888,25.4,30.0492056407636));
#909=LINE('',#908,#907);
#910=CARTESIAN_POINT('',(51.8746018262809,25.4,-24.4505540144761));
#911=VERTEX_POINT('',#910);
#912=CARTESIAN_POINT('',(68.3723857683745,25.4,-33.975554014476));
#913=VERTEX_POINT('',#912);
#914=EDGE_CURVE('E680',#911,#913,#909,.T.);
#915=ORIENTED_EDGE('',*,*,#914,.F.);
#916=DIRECTION('',(0.,-1.,0.));
#917=VECTOR('',#916,1.);
#918=CARTESIAN_POINT('',(51.8746018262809,0.,-24.4505540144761));
#919=LINE('',#918,#917);
#920=EDGE_CURVE('E619',#911,#430,#919,.T.);
#921=ORIENTED_EDGE('',*,*,#920,.T.);
#922=ORIENTED_EDGE('',*,*,#431,.T.);
#923=DIRECTION('',(0.,1.,0.));
#924=VECTOR('',#923,1.);
#925=CARTESIAN_POINT('',(68.3723857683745,0.,-33.975554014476));
#926=LINE('',#925,#924);
#927=EDGE_CURVE('E681',#422,#913,#926,.T.);
#928=ORIENTED_EDGE('',*,*,#927,.T.);
#929=EDGE_LOOP('',(#915,#921,#922,#928));
#930=FACE_BOUND('',#929,.T.);
#931=ADVANCED_FACE('F287',(#905,#930),#894,.F.);
#932=CARTESIAN_POINT('',(-42.5217508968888,25.4,30.0492056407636));
#933=DIRECTION('',(0.,-1.,0.));
#934=DIRECTION('',(1.,0.,0.));
#935=AXIS2_PLACEMENT_3D('',#932,#933,#934);
#936=PLANE('',#935);
#937=DIRECTION('',(0.866025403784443,0.,-0.499999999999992));
#938=VECTOR('',#937,1.);
#939=CARTESIAN_POINT('',(-47.2842508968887,25.4,21.8003136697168));
#940=LINE('',#939,#938);
#941=CARTESIAN_POINT('',(47.112101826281,25.4,-32.699445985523));
#942=VERTEX_POINT('',#941);
#943=CARTESIAN_POINT('',(63.6098857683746,25.4,-42.2244459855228));
#944=VERTEX_POINT('',#943);
#945=EDGE_CURVE('E679',#942,#944,#940,.T.);
#946=ORIENTED_EDGE('',*,*,#945,.F.);
#947=DIRECTION('',(-0.499999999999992,0.,-0.866025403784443));
#948=VECTOR('',#947,1.);
#949=CARTESIAN_POINT('',(52.6683518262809,25.4,-23.0757386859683));
#950=LINE('',#949,#948);
#951=CARTESIAN_POINT('',(46.318351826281,25.4,-34.0742613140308));
#952=VERTEX_POINT('',#951);
#953=EDGE_CURVE('E602',#942,#952,#950,.T.);
#954=ORIENTED_EDGE('',*,*,#953,.T.);
#955=DIRECTION('',(0.866025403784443,0.,-0.499999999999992));
#956=VECTOR('',#955,1.);
#957=CARTESIAN_POINT('',(-87.4510402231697,25.4,43.1575331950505));
#958=LINE('',#957,#956);
#959=EDGE_CURVE('E611',#285,#952,#958,.T.);
#960=ORIENTED_EDGE('',*,*,#959,.F.);
#961=ORIENTED_EDGE('',*,*,#370,.F.);
#962=DIRECTION('',(0.866025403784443,0.,-0.499999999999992));
#963=VECTOR('',#962,1.);
#964=CARTESIAN_POINT('',(-81.1010402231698,25.4,54.156055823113));
#965=LINE('',#964,#963);
#966=CARTESIAN_POINT('',(52.6683518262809,25.4,-23.0757386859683));
#967=VERTEX_POINT('',#966);
#968=EDGE_CURVE('E614',#362,#967,#965,.T.);
#969=ORIENTED_EDGE('',*,*,#968,.T.);
#970=EDGE_CURVE('E603',#967,#911,#950,.T.);
#971=ORIENTED_EDGE('',*,*,#970,.T.);
#972=ORIENTED_EDGE('',*,*,#914,.T.);
#973=DIRECTION('',(-0.499999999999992,0.,-0.866025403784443));
#974=VECTOR('',#973,1.);
#975=CARTESIAN_POINT('',(68.3723857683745,25.4,-33.975554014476));
#976=LINE('',#975,#974);
#977=EDGE_CURVE('E676',#913,#944,#976,.T.);
#978=ORIENTED_EDGE('',*,*,#977,.T.);
#979=EDGE_LOOP('',(#946,#954,#960,#961,#969,#971,#972,#978));
#980=FACE_BOUND('',#979,.T.);
#981=ADVANCED_FACE('F283',(#980),#936,.F.);
#982=CARTESIAN_POINT('',(-47.2842508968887,0.,21.8003136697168));
#983=DIRECTION('',(-0.499999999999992,0.,-0.866025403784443));
#984=DIRECTION('',(-0.866025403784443,0.,0.499999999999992));
#985=AXIS2_PLACEMENT_3D('',#982,#983,#984);
#986=PLANE('',#985);
#987=DIRECTION('',(0.,-1.,0.));
#988=VECTOR('',#987,1.);
#989=CARTESIAN_POINT('',(47.112101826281,0.,-32.6994459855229));
#990=LINE('',#989,#988);
#991=EDGE_CURVE('E226',#942,#406,#990,.T.);
#992=ORIENTED_EDGE('',*,*,#991,.F.);
#993=ORIENTED_EDGE('',*,*,#945,.T.);
#994=DIRECTION('',(0.,1.,0.));
#995=VECTOR('',#994,1.);
#996=CARTESIAN_POINT('',(63.6098857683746,0.,-42.2244459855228));
#997=LINE('',#996,#995);
#998=EDGE_CURVE('E672',#414,#944,#997,.T.);
#999=ORIENTED_EDGE('',*,*,#998,.F.);
#1000=ORIENTED_EDGE('',*,*,#415,.F.);
#1001=EDGE_LOOP('',(#992,#993,#999,#1000));
#1002=FACE_BOUND('',#1001,.T.);
#1003=CARTESIAN_POINT('',(55.3609937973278,9.525,-37.4619459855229));
#1004=DIRECTION('',(-0.499999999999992,0.,-0.866025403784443));
#1005=DIRECTION('',(0.,1.,0.));
#1006=AXIS2_PLACEMENT_3D('',#1003,#1004,#1005);
#1007=CIRCLE('',#1006,4.7625);
#1008=CARTESIAN_POINT('',(55.3609937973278,14.2875,-37.4619459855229));
#1009=VERTEX_POINT('',#1008);
#1010=EDGE_CURVE('E656',#1009,#1009,#1007,.T.);
#1011=ORIENTED_EDGE('',*,*,#1010,.F.);
#1012=EDGE_LOOP('',(#1011));
#1013=FACE_BOUND('',#1012,.T.);
#1014=ADVANCED_FACE('F279',(#1002,#1013),#986,.T.);
#1015=CARTESIAN_POINT('',(68.3723857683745,25.4,-33.975554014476));
#1016=DIRECTION('',(-0.866025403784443,0.,0.499999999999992));
#1017=DIRECTION('',(0.499999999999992,0.,0.866025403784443));
#1018=AXIS2_PLACEMENT_3D('',#1015,#1016,#1017);
#1019=PLANE('',#1018);
#1020=ORIENTED_EDGE('',*,*,#927,.F.);
#1021=ORIENTED_EDGE('',*,*,#423,.F.);
#1022=ORIENTED_EDGE('',*,*,#998,.T.);
#1023=ORIENTED_EDGE('',*,*,#977,.F.);
#1024=EDGE_LOOP('',(#1020,#1021,#1022,#1023));
#1025=FACE_BOUND('',#1024,.T.);
#1026=ADVANCED_FACE('F275',(#1025),#1019,.F.);
#1027=CARTESIAN_POINT('',(-22.3654259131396,9.52499999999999,-94.611945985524));
#1028=DIRECTION('',(-0.500000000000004,0.,0.866025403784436));
#1029=DIRECTION('',(0.866025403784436,0.,0.500000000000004));
#1030=AXIS2_PLACEMENT_3D('',#1027,#1028,#1029);
#1031=CYLINDRICAL_SURFACE('',#1030,4.7625);
#1032=ORIENTED_EDGE('',*,*,#873,.T.);
#1033=EDGE_LOOP('',(#1032));
#1034=FACE_BOUND('',#1033,.T.);
#1035=ORIENTED_EDGE('',*,*,#765,.F.);
#1036=EDGE_LOOP('',(#1035));
#1037=FACE_BOUND('',#1036,.T.);
#1038=ADVANCED_FACE('F271',(#1034,#1037),#1031,.F.);
#1039=CARTESIAN_POINT('',(107.830908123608,9.52499999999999,53.4186114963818));
#1040=DIRECTION('',(-0.499999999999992,0.,-0.866025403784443));
#1041=DIRECTION('',(-0.866025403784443,0.,0.499999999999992));
#1042=AXIS2_PLACEMENT_3D('',#1039,#1040,#1041);
#1043=CYLINDRICAL_SURFACE('',#1042,4.7625);
#1044=ORIENTED_EDGE('',*,*,#1010,.T.);
#1045=EDGE_LOOP('',(#1044));
#1046=FACE_BOUND('',#1045,.T.);
#1047=ORIENTED_EDGE('',*,*,#902,.F.);
#1048=EDGE_LOOP('',(#1047));
#1049=FACE_BOUND('',#1048,.T.);
#1050=ADVANCED_FACE('F260',(#1046,#1049),#1043,.F.);
#1051=CARTESIAN_POINT('',(-46.3183518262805,0.,-34.0742613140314));
#1052=DIRECTION('',(-0.866025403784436,0.,-0.500000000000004));
#1053=DIRECTION('',(-0.500000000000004,0.,0.866025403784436));
#1054=AXIS2_PLACEMENT_3D('',#1051,#1052,#1053);
#1055=PLANE('',#1054);
#1056=ORIENTED_EDGE('',*,*,#816,.F.);
#1057=ORIENTED_EDGE('',*,*,#854,.T.);
#1058=ORIENTED_EDGE('',*,*,#509,.F.);
#1059=DIRECTION('',(0.,-1.,0.));
#1060=VECTOR('',#1059,1.);
#1061=CARTESIAN_POINT('',(-52.6683518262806,25.4,-23.0757386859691));
#1062=LINE('',#1061,#1060);
#1063=EDGE_CURVE('E638',#815,#500,#1062,.T.);
#1064=ORIENTED_EDGE('',*,*,#1063,.F.);
#1065=EDGE_LOOP('',(#1056,#1057,#1058,#1064));
#1066=FACE_BOUND('',#1065,.T.);
#1067=ADVANCED_FACE('F256',(#1066),#1055,.T.);
#1068=CARTESIAN_POINT('',(81.1010402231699,25.4,54.1560558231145));
#1069=DIRECTION('',(0.500000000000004,0.,-0.866025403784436));
#1070=DIRECTION('',(-0.866025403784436,0.,-0.500000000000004));
#1071=AXIS2_PLACEMENT_3D('',#1068,#1069,#1070);
#1072=PLANE('',#1071);
#1073=ORIENTED_EDGE('',*,*,#322,.F.);
#1074=ORIENTED_EDGE('',*,*,#822,.T.);
#1075=ORIENTED_EDGE('',*,*,#1063,.T.);
#1076=ORIENTED_EDGE('',*,*,#501,.F.);
#1077=EDGE_LOOP('',(#1073,#1074,#1075,#1076));
#1078=FACE_BOUND('',#1077,.T.);
#1079=ADVANCED_FACE('F259',(#1078),#1072,.F.);
#1080=ORIENTED_EDGE('',*,*,#783,.F.);
#1081=ORIENTED_EDGE('',*,*,#833,.F.);
#1082=DIRECTION('',(0.,-1.,0.));
#1083=VECTOR('',#1082,1.);
#1084=CARTESIAN_POINT('',(-46.3183518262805,25.4,-34.0742613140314));
#1085=LINE('',#1084,#1083);
#1086=EDGE_CURVE('E631',#830,#536,#1085,.T.);
#1087=ORIENTED_EDGE('',*,*,#1086,.T.);
#1088=ORIENTED_EDGE('',*,*,#537,.F.);
#1089=EDGE_LOOP('',(#1080,#1081,#1087,#1088));
#1090=FACE_BOUND('',#1089,.T.);
#1091=ADVANCED_FACE('F262',(#1090),#1055,.T.);
#1092=CARTESIAN_POINT('',(87.4510402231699,25.4,43.1575331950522));
#1093=DIRECTION('',(0.500000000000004,0.,-0.866025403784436));
#1094=DIRECTION('',(-0.866025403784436,0.,-0.500000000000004));
#1095=AXIS2_PLACEMENT_3D('',#1092,#1093,#1094);
#1096=PLANE('',#1095);
#1097=ORIENTED_EDGE('',*,*,#831,.F.);
#1098=ORIENTED_EDGE('',*,*,#305,.T.);
#1099=ORIENTED_EDGE('',*,*,#543,.T.);
#1100=ORIENTED_EDGE('',*,*,#1086,.F.);
#1101=EDGE_LOOP('',(#1097,#1098,#1099,#1100));
#1102=FACE_BOUND('',#1101,.T.);
#1103=ADVANCED_FACE('F247',(#1102),#1096,.T.);
#1104=CARTESIAN_POINT('',(52.6683518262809,0.,-23.0757386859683));
#1105=DIRECTION('',(0.866025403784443,0.,-0.499999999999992));
#1106=DIRECTION('',(-0.499999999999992,0.,-0.866025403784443));
#1107=AXIS2_PLACEMENT_3D('',#1104,#1105,#1106);
#1108=PLANE('',#1107);
#1109=ORIENTED_EDGE('',*,*,#953,.F.);
#1110=ORIENTED_EDGE('',*,*,#991,.T.);
#1111=ORIENTED_EDGE('',*,*,#407,.F.);
#1112=DIRECTION('',(0.,-1.,0.));
#1113=VECTOR('',#1112,1.);
#1114=CARTESIAN_POINT('',(46.318351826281,25.4,-34.0742613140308));
#1115=LINE('',#1114,#1113);
#1116=EDGE_CURVE('E606',#952,#398,#1115,.T.);
#1117=ORIENTED_EDGE('',*,*,#1116,.F.);
#1118=EDGE_LOOP('',(#1109,#1110,#1111,#1117));
#1119=FACE_BOUND('',#1118,.T.);
#1120=ADVANCED_FACE('F242',(#1119),#1108,.T.);
#1121=CARTESIAN_POINT('',(-87.4510402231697,25.4,43.1575331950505));
#1122=DIRECTION('',(0.499999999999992,0.,0.866025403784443));
#1123=DIRECTION('',(0.866025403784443,0.,-0.499999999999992));
#1124=AXIS2_PLACEMENT_3D('',#1121,#1122,#1123);
#1125=PLANE('',#1124);
#1126=ORIENTED_EDGE('',*,*,#288,.F.);
#1127=ORIENTED_EDGE('',*,*,#959,.T.);
#1128=ORIENTED_EDGE('',*,*,#1116,.T.);
#1129=ORIENTED_EDGE('',*,*,#399,.F.);
#1130=EDGE_LOOP('',(#1126,#1127,#1128,#1129));
#1131=FACE_BOUND('',#1130,.T.);
#1132=ADVANCED_FACE('F246',(#1131),#1125,.F.);
#1133=ORIENTED_EDGE('',*,*,#920,.F.);
#1134=ORIENTED_EDGE('',*,*,#970,.F.);
#1135=DIRECTION('',(0.,-1.,0.));
#1136=VECTOR('',#1135,1.);
#1137=CARTESIAN_POINT('',(52.6683518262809,25.4,-23.0757386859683));
#1138=LINE('',#1137,#1136);
#1139=EDGE_CURVE('E599',#967,#434,#1138,.T.);
#1140=ORIENTED_EDGE('',*,*,#1139,.T.);
#1141=ORIENTED_EDGE('',*,*,#435,.F.);
#1142=EDGE_LOOP('',(#1133,#1134,#1140,#1141));
#1143=FACE_BOUND('',#1142,.T.);
#1144=ADVANCED_FACE('F249',(#1143),#1108,.T.);
#1145=CARTESIAN_POINT('',(-81.1010402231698,25.4,54.156055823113));
#1146=DIRECTION('',(0.499999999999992,0.,0.866025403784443));
#1147=DIRECTION('',(0.866025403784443,0.,-0.499999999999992));
#1148=AXIS2_PLACEMENT_3D('',#1145,#1146,#1147);
#1149=PLANE('',#1148);
#1150=ORIENTED_EDGE('',*,*,#968,.F.);
#1151=ORIENTED_EDGE('',*,*,#363,.T.);
#1152=ORIENTED_EDGE('',*,*,#441,.T.);
#1153=ORIENTED_EDGE('',*,*,#1139,.F.);
#1154=EDGE_LOOP('',(#1150,#1151,#1152,#1153));
#1155=FACE_BOUND('',#1154,.T.);
#1156=ADVANCED_FACE('F241',(#1155),#1149,.T.);
#1157=CARTESIAN_POINT('',(0.,38.1,15.24));
#1158=DIRECTION('',(0.,0.,1.));
#1159=DIRECTION('',(0.,-1.,0.));
#1160=AXIS2_PLACEMENT_3D('',#1157,#1158,#1159);
#1161=CYLINDRICAL_SURFACE('',#1160,7.1501);
#1162=ORIENTED_EDGE('',*,*,#51,.F.);
#1163=ORIENTED_EDGE('',*,*,#225,.F.);
#1164=EDGE_LOOP('',(#1162,#1163));
#1165=FACE_BOUND('',#1164,.T.);
#1166=ADVANCED_FACE('F221',(#1165),#1161,.F.);
#1167=ORIENTED_EDGE('',*,*,#41,.F.);
#1168=ORIENTED_EDGE('',*,*,#265,.F.);
#1169=EDGE_LOOP('',(#1167,#1168));
#1170=FACE_BOUND('',#1169,.T.);
#1171=ADVANCED_FACE('F240',(#1170),#1161,.F.);
#1172=CARTESIAN_POINT('',(0.,38.1,15.24));
#1173=DIRECTION('',(0.,0.,1.));
#1174=DIRECTION('',(0.,-1.,0.));
#1175=AXIS2_PLACEMENT_3D('',#1172,#1173,#1174);
#1176=CYLINDRICAL_SURFACE('',#1175,3.17499725);
#1177=ORIENTED_EDGE('',*,*,#175,.F.);
#1178=EDGE_LOOP('',(#1177));
#1179=FACE_BOUND('',#1178,.T.);
#1180=ORIENTED_EDGE('',*,*,#62,.T.);
#1181=EDGE_LOOP('',(#1180));
#1182=FACE_BOUND('',#1181,.T.);
#1183=ADVANCED_FACE('F564',(#1179,#1182),#1176,.F.);
#1184=CLOSED_SHELL('',(#66,#179,#374,#386,#550,#581,#616,#659,#687,#699,#716,#728,#740,#752,
#794,#844,#877,#889,#931,#981,#1014,#1026,#1038,#1050,#1067,#1079,#1091,#1103,#1120,#1132,#1144,
#1156,#1166,#1171,#1183));
#1185=MANIFOLD_SOLID_BREP('B2',#1184);
#1186=ADVANCED_BREP_SHAPE_REPRESENTATION('',(#18,#1185),#14);
#1187=SHAPE_DEFINITION_REPRESENTATION(#9,#1186);
ENDSEC;
END-ISO-10303-21;
